VERSION 5.7 ;
  NOWIREEXTENSIONATPIN ON ;
  DIVIDERCHAR "/" ;
  BUSBITCHARS "[]" ;
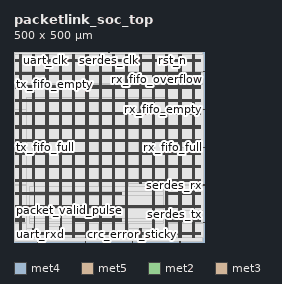
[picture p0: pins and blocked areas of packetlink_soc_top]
MACRO packetlink_soc_top
  CLASS BLOCK ;
  FOREIGN packetlink_soc_top ;
  ORIGIN 0.000 0.000 ;
  SIZE 500.000 BY 500.000 ;
  PIN VGND
    DIRECTION INOUT ;
    USE GROUND ;
    PORT
      LAYER met4 ;
        RECT 17.760 10.640 19.760 492.560 ;
    END
    PORT
      LAYER met4 ;
        RECT 52.760 10.640 54.760 492.560 ;
    END
    PORT
      LAYER met4 ;
        RECT 87.760 10.640 89.760 492.560 ;
    END
    PORT
      LAYER met4 ;
        RECT 122.760 10.640 124.760 492.560 ;
    END
    PORT
      LAYER met4 ;
        RECT 157.760 10.640 159.760 492.560 ;
    END
    PORT
      LAYER met4 ;
        RECT 192.760 10.640 194.760 492.560 ;
    END
    PORT
      LAYER met4 ;
        RECT 227.760 10.640 229.760 492.560 ;
    END
    PORT
      LAYER met4 ;
        RECT 262.760 10.640 264.760 492.560 ;
    END
    PORT
      LAYER met4 ;
        RECT 297.760 10.640 299.760 492.560 ;
    END
    PORT
      LAYER met4 ;
        RECT 332.760 10.640 334.760 35.040 ;
    END
    PORT
      LAYER met4 ;
        RECT 332.760 154.640 334.760 492.560 ;
    END
    PORT
      LAYER met4 ;
        RECT 367.760 10.640 369.760 492.560 ;
    END
    PORT
      LAYER met4 ;
        RECT 402.760 10.640 404.760 492.560 ;
    END
    PORT
      LAYER met4 ;
        RECT 437.760 10.640 439.760 492.560 ;
    END
    PORT
      LAYER met4 ;
        RECT 472.760 10.640 474.760 492.560 ;
    END
    PORT
      LAYER met5 ;
        RECT 5.060 23.580 489.900 25.580 ;
    END
    PORT
      LAYER met5 ;
        RECT 5.060 58.580 27.320 60.580 ;
    END
    PORT
      LAYER met5 ;
        RECT 5.060 93.580 489.900 95.580 ;
    END
    PORT
      LAYER met5 ;
        RECT 5.060 128.580 282.320 130.580 ;
    END
    PORT
      LAYER met5 ;
        RECT 5.060 163.580 489.900 165.580 ;
    END
    PORT
      LAYER met5 ;
        RECT 5.060 198.580 489.900 200.580 ;
    END
    PORT
      LAYER met5 ;
        RECT 5.060 233.580 489.900 235.580 ;
    END
    PORT
      LAYER met5 ;
        RECT 5.060 268.580 489.900 270.580 ;
    END
    PORT
      LAYER met5 ;
        RECT 5.060 303.580 489.900 305.580 ;
    END
    PORT
      LAYER met5 ;
        RECT 5.060 338.580 489.900 340.580 ;
    END
    PORT
      LAYER met5 ;
        RECT 5.060 373.580 489.900 375.580 ;
    END
    PORT
      LAYER met5 ;
        RECT 5.060 408.580 489.900 410.580 ;
    END
    PORT
      LAYER met5 ;
        RECT 5.060 443.580 489.900 445.580 ;
    END
    PORT
      LAYER met5 ;
        RECT 5.060 478.580 489.900 480.580 ;
    END
    PORT
      LAYER met5 ;
        RECT 159.980 58.580 282.320 60.580 ;
    END
    PORT
      LAYER met5 ;
        RECT 406.700 58.580 489.900 60.580 ;
    END
    PORT
      LAYER met5 ;
        RECT 406.700 128.580 489.900 130.580 ;
    END
  END VGND
  PIN VPWR
    DIRECTION INOUT ;
    USE POWER ;
    PORT
      LAYER met4 ;
        RECT 14.060 10.640 16.060 492.560 ;
    END
    PORT
      LAYER met4 ;
        RECT 49.060 10.640 51.060 35.040 ;
    END
    PORT
      LAYER met4 ;
        RECT 49.060 162.800 51.060 492.560 ;
    END
    PORT
      LAYER met4 ;
        RECT 84.060 10.640 86.060 492.560 ;
    END
    PORT
      LAYER met4 ;
        RECT 119.060 10.640 121.060 39.835 ;
    END
    PORT
      LAYER met4 ;
        RECT 119.060 79.125 121.060 492.560 ;
    END
    PORT
      LAYER met4 ;
        RECT 154.060 10.640 156.060 492.560 ;
    END
    PORT
      LAYER met4 ;
        RECT 189.060 10.640 191.060 492.560 ;
    END
    PORT
      LAYER met4 ;
        RECT 224.060 10.640 226.060 492.560 ;
    END
    PORT
      LAYER met4 ;
        RECT 259.060 10.640 261.060 492.560 ;
    END
    PORT
      LAYER met4 ;
        RECT 294.060 10.640 296.060 492.560 ;
    END
    PORT
      LAYER met4 ;
        RECT 329.060 10.640 331.060 35.040 ;
    END
    PORT
      LAYER met4 ;
        RECT 329.060 154.640 331.060 492.560 ;
    END
    PORT
      LAYER met4 ;
        RECT 364.060 10.640 366.060 492.560 ;
    END
    PORT
      LAYER met4 ;
        RECT 399.060 10.640 401.060 492.560 ;
    END
    PORT
      LAYER met4 ;
        RECT 434.060 10.640 436.060 492.560 ;
    END
    PORT
      LAYER met4 ;
        RECT 469.060 10.640 471.060 492.560 ;
    END
    PORT
      LAYER met5 ;
        RECT 5.060 19.880 489.900 21.880 ;
    END
    PORT
      LAYER met5 ;
        RECT 5.060 54.880 27.320 56.880 ;
    END
    PORT
      LAYER met5 ;
        RECT 5.060 89.880 489.900 91.880 ;
    END
    PORT
      LAYER met5 ;
        RECT 5.060 124.880 282.320 126.880 ;
    END
    PORT
      LAYER met5 ;
        RECT 5.060 159.880 489.900 161.880 ;
    END
    PORT
      LAYER met5 ;
        RECT 5.060 194.880 489.900 196.880 ;
    END
    PORT
      LAYER met5 ;
        RECT 5.060 229.880 489.900 231.880 ;
    END
    PORT
      LAYER met5 ;
        RECT 5.060 264.880 489.900 266.880 ;
    END
    PORT
      LAYER met5 ;
        RECT 5.060 299.880 489.900 301.880 ;
    END
    PORT
      LAYER met5 ;
        RECT 5.060 334.880 489.900 336.880 ;
    END
    PORT
      LAYER met5 ;
        RECT 5.060 369.880 489.900 371.880 ;
    END
    PORT
      LAYER met5 ;
        RECT 5.060 404.880 489.900 406.880 ;
    END
    PORT
      LAYER met5 ;
        RECT 5.060 439.880 489.900 441.880 ;
    END
    PORT
      LAYER met5 ;
        RECT 5.060 474.880 489.900 476.880 ;
    END
    PORT
      LAYER met5 ;
        RECT 159.980 54.880 282.320 56.880 ;
    END
    PORT
      LAYER met5 ;
        RECT 406.700 54.880 489.900 56.880 ;
    END
    PORT
      LAYER met5 ;
        RECT 406.700 124.880 489.900 126.880 ;
    END
  END VPWR
  PIN crc_error_sticky
    DIRECTION OUTPUT ;
    USE SIGNAL ;
    ANTENNADIFFAREA 0.445500 ;
    PORT
      LAYER met2 ;
        RECT 311.970 0.000 312.250 0.280 ;
    END
  END crc_error_sticky
  PIN packet_valid_pulse
    DIRECTION OUTPUT ;
    USE SIGNAL ;
    ANTENNADIFFAREA 0.445500 ;
    PORT
      LAYER met3 ;
        RECT 0.000 83.000 0.600 83.600 ;
    END
  END packet_valid_pulse
  PIN rst_n
    DIRECTION INPUT ;
    USE SIGNAL ;
    ANTENNAGATEAREA 0.159000 ;
    PORT
      LAYER met2 ;
        RECT 416.390 499.720 416.670 500.000 ;
    END
  END rst_n
  PIN rx_fifo_empty
    DIRECTION OUTPUT ;
    USE SIGNAL ;
    ANTENNADIFFAREA 0.445500 ;
    PORT
      LAYER met3 ;
        RECT 499.400 348.200 500.000 348.800 ;
    END
  END rx_fifo_empty
  PIN rx_fifo_full
    DIRECTION OUTPUT ;
    USE SIGNAL ;
    ANTENNADIFFAREA 0.445500 ;
    PORT
      LAYER met3 ;
        RECT 499.400 248.920 500.000 249.520 ;
    END
  END rx_fifo_full
  PIN rx_fifo_overflow
    DIRECTION OUTPUT ;
    USE SIGNAL ;
    ANTENNADIFFAREA 0.445500 ;
    PORT
      LAYER met3 ;
        RECT 499.400 447.480 500.000 448.080 ;
    END
  END rx_fifo_overflow
  PIN serdes_clk
    DIRECTION INPUT ;
    USE SIGNAL ;
    ANTENNAGATEAREA 1.704000 ;
    PORT
      LAYER met2 ;
        RECT 249.870 499.720 250.150 500.000 ;
    END
  END serdes_clk
  PIN serdes_rx
    DIRECTION INPUT ;
    USE SIGNAL ;
    ANTENNAGATEAREA 0.196500 ;
    PORT
      LAYER met3 ;
        RECT 499.400 149.640 500.000 150.240 ;
    END
  END serdes_rx
  PIN serdes_tx
    DIRECTION OUTPUT ;
    USE SIGNAL ;
    ANTENNADIFFAREA 1.336500 ;
    PORT
      LAYER met3 ;
        RECT 499.400 50.360 500.000 50.960 ;
    END
  END serdes_tx
  PIN tx_fifo_empty
    DIRECTION OUTPUT ;
    USE SIGNAL ;
    ANTENNADIFFAREA 1.782000 ;
    PORT
      LAYER met3 ;
        RECT 0.000 414.840 0.600 415.440 ;
    END
  END tx_fifo_empty
  PIN tx_fifo_full
    DIRECTION OUTPUT ;
    USE SIGNAL ;
    ANTENNADIFFAREA 0.445500 ;
    PORT
      LAYER met3 ;
        RECT 0.000 248.920 0.600 249.520 ;
    END
  END tx_fifo_full
  PIN tx_fifo_overflow
    DIRECTION OUTPUT ;
    USE SIGNAL ;
    ANTENNADIFFAREA 0.445500 ;
    PORT
      LAYER met2 ;
        RECT 436.630 0.000 436.910 0.280 ;
    END
  END tx_fifo_overflow
  PIN uart_clk
    DIRECTION INPUT ;
    USE SIGNAL ;
    ANTENNAGATEAREA 1.704000 ;
    PORT
      LAYER met2 ;
        RECT 83.350 499.720 83.630 500.000 ;
    END
  END uart_clk
  PIN uart_rxd
    DIRECTION INPUT ;
    USE SIGNAL ;
    ANTENNAGATEAREA 0.213000 ;
    PORT
      LAYER met2 ;
        RECT 62.650 0.000 62.930 0.280 ;
    END
  END uart_rxd
  PIN uart_txd
    DIRECTION OUTPUT ;
    USE SIGNAL ;
    ANTENNADIFFAREA 0.445500 ;
    PORT
      LAYER met2 ;
        RECT 187.310 0.000 187.590 0.280 ;
    END
  END uart_txd
  OBS
      LAYER nwell ;
        RECT 4.870 10.795 490.090 492.510 ;
      LAYER li1 ;
        RECT 5.060 10.795 489.900 492.405 ;
      LAYER met1 ;
        RECT 0.990 10.640 495.810 492.560 ;
      LAYER met2 ;
        RECT 1.010 499.440 83.070 499.720 ;
        RECT 83.910 499.440 249.590 499.720 ;
        RECT 250.430 499.440 416.110 499.720 ;
        RECT 416.950 499.440 495.790 499.720 ;
        RECT 1.010 0.560 495.790 499.440 ;
        RECT 1.010 0.280 62.370 0.560 ;
        RECT 63.210 0.280 187.030 0.560 ;
        RECT 187.870 0.280 311.690 0.560 ;
        RECT 312.530 0.280 436.350 0.560 ;
        RECT 437.190 0.280 495.790 0.560 ;
      LAYER met3 ;
        RECT 0.600 448.480 499.400 492.485 ;
        RECT 0.600 447.080 499.000 448.480 ;
        RECT 0.600 415.840 499.400 447.080 ;
        RECT 1.000 414.440 499.400 415.840 ;
        RECT 0.600 349.200 499.400 414.440 ;
        RECT 0.600 347.800 499.000 349.200 ;
        RECT 0.600 249.920 499.400 347.800 ;
        RECT 1.000 248.520 499.000 249.920 ;
        RECT 0.600 150.640 499.400 248.520 ;
        RECT 0.600 149.240 499.000 150.640 ;
        RECT 0.600 84.000 499.400 149.240 ;
        RECT 1.000 82.600 499.400 84.000 ;
        RECT 0.600 51.360 499.400 82.600 ;
        RECT 0.600 49.960 499.000 51.360 ;
        RECT 0.600 10.715 499.400 49.960 ;
      LAYER met4 ;
        RECT 33.430 162.400 48.660 379.945 ;
        RECT 51.460 162.400 52.360 379.945 ;
        RECT 33.430 35.440 52.360 162.400 ;
        RECT 33.430 13.095 48.660 35.440 ;
        RECT 51.460 13.095 52.360 35.440 ;
        RECT 55.160 13.095 83.660 379.945 ;
        RECT 86.460 13.095 87.360 379.945 ;
        RECT 90.160 78.725 118.660 379.945 ;
        RECT 121.460 78.725 122.360 379.945 ;
        RECT 90.160 40.235 122.360 78.725 ;
        RECT 90.160 13.095 118.660 40.235 ;
        RECT 121.460 13.095 122.360 40.235 ;
        RECT 125.160 13.095 153.660 379.945 ;
        RECT 156.460 13.095 157.360 379.945 ;
        RECT 160.160 13.095 188.660 379.945 ;
        RECT 191.460 13.095 192.360 379.945 ;
        RECT 195.160 13.095 223.660 379.945 ;
        RECT 226.460 13.095 227.360 379.945 ;
        RECT 230.160 13.095 258.660 379.945 ;
        RECT 261.460 13.095 262.360 379.945 ;
        RECT 265.160 13.095 293.660 379.945 ;
        RECT 296.460 13.095 297.360 379.945 ;
        RECT 300.160 154.240 328.660 379.945 ;
        RECT 331.460 154.240 332.360 379.945 ;
        RECT 335.160 154.240 363.660 379.945 ;
        RECT 300.160 35.440 363.660 154.240 ;
        RECT 300.160 13.095 328.660 35.440 ;
        RECT 331.460 13.095 332.360 35.440 ;
        RECT 335.160 13.095 363.660 35.440 ;
        RECT 366.460 13.095 367.360 379.945 ;
        RECT 370.160 13.095 398.660 379.945 ;
        RECT 401.460 13.095 402.360 379.945 ;
        RECT 405.160 13.095 406.345 379.945 ;
      LAYER met5 ;
        RECT 40.520 132.180 393.500 145.580 ;
        RECT 283.920 123.280 393.500 132.180 ;
        RECT 40.520 97.180 393.500 123.280 ;
        RECT 40.520 62.180 393.500 88.280 ;
        RECT 40.520 53.280 158.380 62.180 ;
        RECT 283.920 53.280 393.500 62.180 ;
        RECT 40.520 49.880 393.500 53.280 ;
  END
END packetlink_soc_top
END LIBRARY

